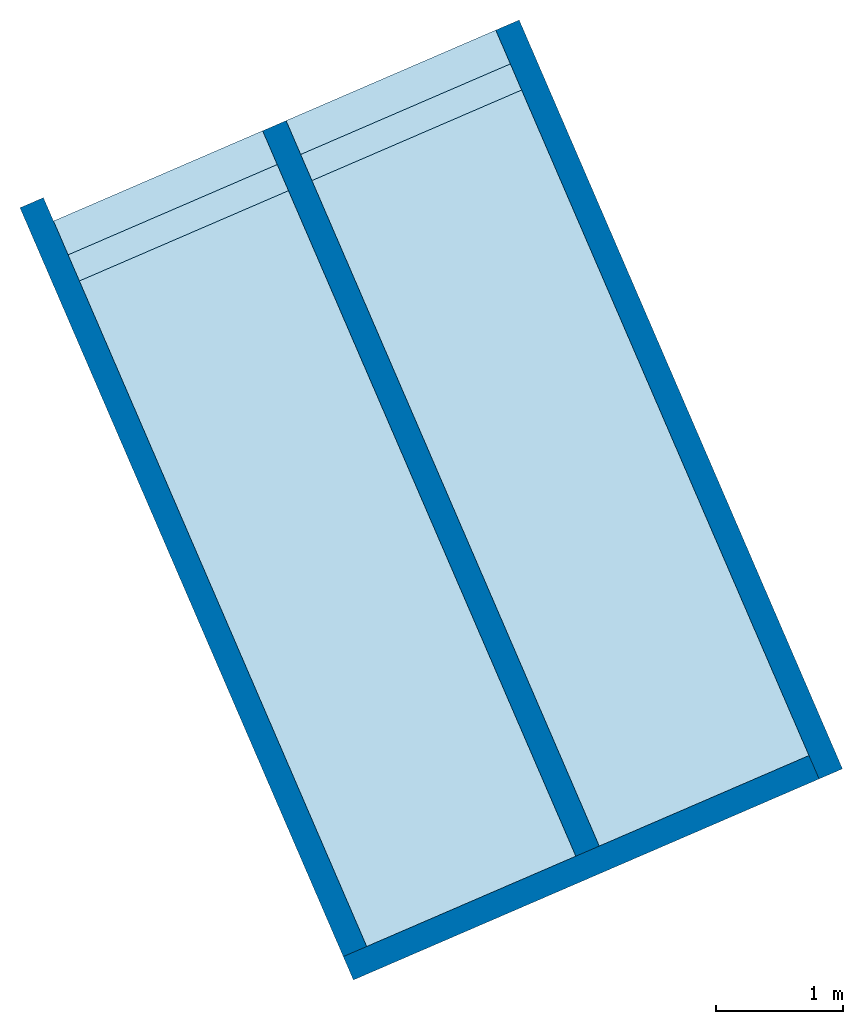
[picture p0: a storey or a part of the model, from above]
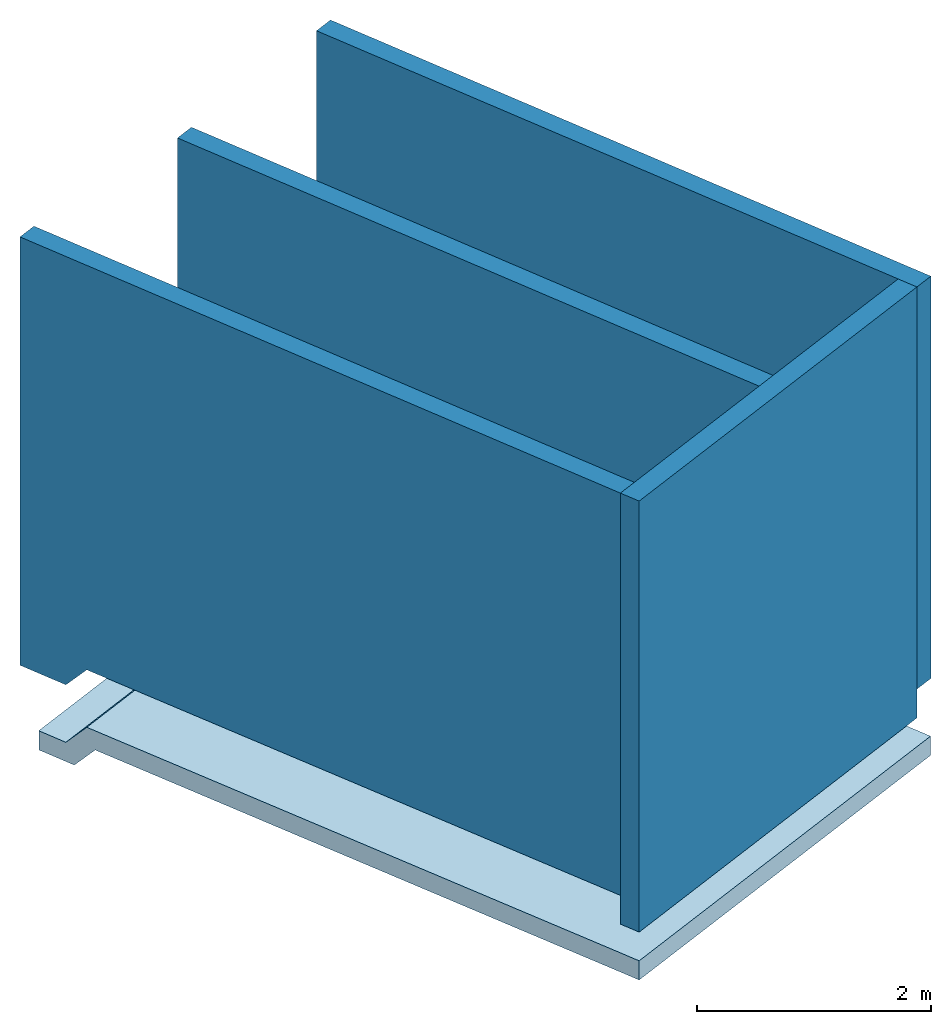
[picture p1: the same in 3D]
Properties of the parts of a building model (IFC4)

# File
Description: ViewDefinition [ReferenceView_V1.2], RevitIdentifiers [ContentGUID: b144eeac-5747-47a0-b632-81c9454398bd, VersionGUID: 75be5fcd-6818-4028-9b9e-a30bbd643937, NumberOfSaves: 4], CoordinateReference [CoordinateBase: Shared Coordinates, ProjectSite: Interno]
File name: C:\Users\Joaquin\Dropbox\BuildingProjects\2024 - Construcción Cesfam Coyhaique Con Sar Adosado\2_Modelos\all_models_2025-1-24_23.4.48\CCY_COOR-CCY_EST_tecnico_Enriched.ifc
Time: 2025-10-27T11:57:53-04:00
Written by: ODA SDAI 24.12
Made in: Autodesk Revit 25.4.30.30 (ENG) - IFC 25.4.3.0

# IfcProject, 2016_03
LongName: CESFAM Coyhaique; Phase: 2

# IfcSite, Default
RefLatitude: 42, 21, 31, 181945; RefLongitude: -71, -3, -24, -263305; RefElevation: 0 m
Pset_SiteCommon - Reference: Project Information
Other - Category: Project Information; Client Name: Servicio de Salud Aysén; Project Address: Calle 2, s/n. Lote 1C.; Project Issue Date: Marzo 2017; Project Name: CESFAM Coyhaique; Project Number: 2016_03; Project Status: 2
Identity Data - Author: Astudillo y Aparicio Asociados Ltda.; Building Name: CESFAM Coyhaique; Organization Description: Arquitectura e ingeniería integrada; Organization Name: Astudillo y Aparicio Asociados Ltda.

# IfcBuilding, CESFAM Coyhaique
LongName: CESFAM Coyhaique
Pset_BuildingCommon - Reference: Project Information; NumberOfStoreys: 6
Pset_BuildingElementProxyCommon - Reference: Project Information; IsExternal: no
Pset_BuildingSystemCommon - Reference: Project Information
Other - Category: Project Information; Client Name: Servicio de Salud Aysén; Project Address: Calle 2, s/n. Lote 1C.; Project Issue Date: Marzo 2017; Project Name: CESFAM Coyhaique; Project Number: 2016_03; Project Status: 2
Identity Data - Author: Astudillo y Aparicio Asociados Ltda.; Building Name: CESFAM Coyhaique; Organization Description: Arquitectura e ingeniería integrada; Organization Name: Astudillo y Aparicio Asociados Ltda.

# IfcBuildingStorey: Level:Nivel 8mm (6)
In: CESFAM Coyhaique
Other - Category: Levels; Family: Level; Family and Type: Level: Nivel 8mm; Type: Nivel 8mm; Type Id: 762418
Dimensions - Computation Height: 0 m
Identity Data - Structural: no; Building Story: yes
Other(Type) - Category: Levels; Family Name: Level
Constraints(Type) - Elevation Base: Survey Point
Graphics(Type) - Color: 0; Line Pattern: Center; Line Weight: 1; Symbol: Sim_NivelElev : Esc_200; Symbol at End 1 Default: no; Symbol at End 2 Default: yes
Identity Data(Type) - Type Name: Nivel 8mm
Name | LongName = Name | Elevation (m) | Constraints, Elevation (m)
Subterráneo 1 | Subterráneo 1 | -3.8 | 313.5
Base Estanques | Base Estanques | -3.55 | 313.75
Tunel | Tunel | -1.95 | 315.35
Nivel 1 | Nivel 1 | -0.55 | 316.75
Nivel 2 | Nivel 2 | 1.1 | 318.4
Nivel 3 | Nivel 3 | 2.7 | 320

# IfcBeam: M_W Shapes:W220X110mm (28)
In: Nivel 3
Type - PredefinedType: BEAM; Material: Steel, 45-345
Type - Other - Category: Structural Framing; Family Name: M_W Shapes
Type - Identity Data - Code Name: AISC 14.1; OmniClass Number: 23.25.30.11.14.14; OmniClass Title: Beams; Section Name Key: W12x26; Type Name: W220X110mm
Type - Structural - Section Shape: 6
Type - Structural Analysis - Elastic Modulus strong axis: 0.000547 m3; Elastic Modulus weak axis: 0.0000875 m3; Moment of Inertia strong axis: 0.0000849 m4; Moment of Inertia weak axis: 0.0000072 m4; Nominal Weight: 379.516 kg/s2; Perimeter: 1.25 m; Plastic Modulus strong axis: 0.00061 m3; Plastic Modulus weak axis: 0.000134 m3; Section Area: 0.00494 m2; Torsional Moment of Inertia: 1.25e-07 m4; Warping Constant: 1.63e-07 m6
Type - Structural Section Geometry - Centroid Horizontal: 0.055 m; Centroid Vertical: 0.11 m; Flange Thickness: 0.00965 m; Height: 0.22 m; Web Fillet: 0.00765 m; Web Thickness: 0.00584 m; Width: 0.11 m
Type - Pset_BeamCommon - LoadBearing: yes
Classification: B103 (FEMAP58); Material: Steel, 45-345; Steel, 45-345
Pset_BeamCommon - IsExternal: no; Reference: M_W Shapes:W220X110mm; Slope: 0 deg; Roll: 0 deg
Pset_EnvironmentalImpactIndicators - Reference: M_W Shapes:W220X110mm; sets with these values: 2
Qto_BeamBaseQuantities - CrossSectionArea: 0.00334538 m2
Other - Family: M_W Shapes; Family and Type: M_W Shapes: W220X110mm; Type: W220X110mm; Type Id: 849998
Constraints - Cross-Section Rotation: 0 deg; End Level Offset: 0 m; Orientation: Normal; Reference Level: Nivel 3; Reference Level Elevation: 2.7 m; Start Level Offset: 0 m; Work Plane: Level : Nivel 3
Dimensions - Elevation at Bottom: 2.33 m; Elevation at Top: 2.55 m
Materials and Finishes - Structural Material: Steel, 45-345
Phasing - Phase Created: New Construction
Structural - Stick Symbol Location: Center of Geometry; Structural Usage: Other
Geometric Position - Join Status: Both joins enabled; y Justification: Origin; y Offset Value: 0 m; yz Justification: Uniform; z Justification: Top; z Offset Value: -0.15 m
AboveGround - AboveGround: yes
Name (M_W Shapes:W220X110mm:...) | Span (m) = Qto_BeamBaseQuantities, Length (m) = Dimensions, Length (m) | OuterSurfaceArea (m2) | GrossSurfaceArea (m2) | NetSurfaceArea (m2) | GrossVolume (m3) | NetVolume (m3) = Volume (m3) | Cut Length (m) | Weight (kg) | End Extension (m) | Start Extension (m) | Start Join Cutback (m) | End Join Cutback (m)
833402 | 4.0749 | 3.4269 | 3.43359 | 3.43359 | 0.0134056 | 0.0134054 | 4.0072 | 155.376 | 0 | 0 | 0.0127
845368 | 3.98 | 3.28049 | 3.28719 | 3.28719 | 0.0128329 | 0.0128327 | 3.836 | 148.738 | -0.127 | -0.127
850091 | 1.05 | 0.887085 | 0.893776 | 0.893776 | 0.00347016 | 0.00347011 | 1.0373 | 40.2206 | -0.0166152 | 0 |  | 0.0127
850224 | 1.05 | 0.782153 | 0.788844 | 0.788844 | 0.00305968 | 0.00305964 | 0.9146 | 35.463 | -0.0166152 | 0 | 0.0127 | 0.0127
850260 | 6.085 | 5.08802 | 5.09471 | 5.09471 | 0.0199037 | 0.0199076 | 5.9496 | 230.692 | -0.0166152 | 0 | 0.0127 | 0.0127
850262 | 6.085 | 5.08802 | 5.09471 | 5.09471 | 0.0199037 | 0.0199076 | 5.9496 | 230.692 | -0.0166152 | 0 | 0.0127 | 0.0127
850275 | 3.01 | 2.45832 | 2.46501 | 2.46501 | 0.00961662 | 0.00961854 | 2.8746 | 111.461 | -0.0166152 | 0 | 0.0127 | 0.0127
850277 | 3.01 | 2.45832 | 2.46501 | 2.46501 | 0.00961662 | 0.00961854 | 2.8746 | 111.461 | -0.0166152 | 0 | 0.0127 | 0.0127
850289 | 3.99 | 3.2964 | 3.30309 | 3.3031 | 0.0128951 | 0.0128977 | 3.8546 | 149.459 | -0.0166152 | 0 | 0.0127 | 0.0127
850291 | 3.99 | 3.2964 | 3.30309 | 3.3031 | 0.0128951 | 0.0128977 | 3.8546 | 149.459 | -0.0166152 | 0 | 0.0127 | 0.0127
850303 | 5 | 4.16014 | 4.16683 | 4.16683 | 0.0162739 | 0.0162772 | 4.8646 | 188.621 | -0.0166152 | 0 | 0.0127 | 0.0127
850305 | 5 | 4.16014 | 4.16683 | 4.16683 | 0.0162739 | 0.0162772 | 4.8646 | 188.621 | -0.0166152 | 0 | 0.0127 | 0.0127
850319 | 4.2 | 3.47599 | 3.48268 | 3.48269 | 0.0135976 | 0.0136003 | 4.0646 | 157.602 | -0.0166152 | 0 | 0.0127 | 0.0127
850321 | 4.2 | 3.47599 | 3.48268 | 3.48269 | 0.0135976 | 0.0136003 | 4.0646 | 157.602 | -0.0166152 | 0 | 0.0127 | 0.0127
850335 | 4 | 3.30495 | 3.31164 | 3.31165 | 0.0129285 | 0.0129311 | 3.8646 | 149.847 | -0.0166152 | 0 | 0.0127 | 0.0127
850337 | 4 | 3.30495 | 3.31164 | 3.31165 | 0.0129285 | 0.0129311 | 3.8646 | 149.847 | -0.0166152 | 0 | 0.0127 | 0.0127
850355 | 4.4 | 3.64703 | 3.65372 | 3.65372 | 0.0142667 | 0.0142695 | 4.2646 | 165.357 | -0.0166152 | 0 | 0.0127 | 0.0127
850357 | 4.4 | 3.64703 | 3.65372 | 3.65372 | 0.0142667 | 0.0142695 | 4.2646 | 165.357 | -0.0166152 | 0 | 0.0127 | 0.0127
850370 | 2.785 | 2.2659 | 2.27259 | 2.2726 | 0.00886391 | 0.00886568 | 2.6496 | 102.736 | -0.0166152 | 0 | 0.0127 | 0.0127
850372 | 2.785 | 2.2659 | 2.27259 | 2.2726 | 0.00886391 | 0.00886568 | 2.6496 | 102.736 | -0.0166152 | 0 | 0.0127 | 0.0127
850586 | 3.98 | 3.28049 | 3.28719 | 3.28719 | 0.0128329 | 0.0128327 | 3.836 | 148.738 | -0.127 | -0.127
850598 | 3.98 | 3.28049 | 3.28719 | 3.28719 | 0.0128329 | 0.0128327 | 3.836 | 148.738 | -0.127 | -0.127
850610 | 3.98 | 3.28049 | 3.28719 | 3.28719 | 0.0128329 | 0.0128327 | 3.836 | 148.738 | -0.127 | -0.127
850622 | 3.98 | 3.28049 | 3.28719 | 3.28719 | 0.0128329 | 0.0128327 | 3.836 | 148.738 | -0.127 | -0.127
850634 | 3.98 | 3.28049 | 3.28719 | 3.28719 | 0.0128329 | 0.0128327 | 3.836 | 148.738 | -0.127 | -0.127
850646 | 3.98 | 3.28049 | 3.28719 | 3.28719 | 0.0128329 | 0.0128327 | 3.836 | 148.738 | -0.127 | -0.127
850658 | 3.98 | 3.28049 | 3.28719 | 3.28719 | 0.0128329 | 0.0128327 | 3.836 | 148.738 | -0.127 | -0.127
850670 | 3.98 | 3.28049 | 3.28719 | 3.28719 | 0.0128329 | 0.0128327 | 3.836 | 148.738 | -0.127 | -0.127

# IfcColumn: M_Concrete-Square-Column:600 x 600mm (7)
In: Subterráneo 1
Type - PredefinedType: COLUMN; Material: HA
Type - Other - Category: Structural Columns; Family Name: M_Concrete-Square-Column
Type - Data - Sup. en planta: 0.36 m2
Type - Dimensions - b: 0.6 m
Type - Identity Data - OmniClass Number: 23.25.30.11.14.11; OmniClass Title: Columns; Type Name: 600 x 600mm
Type - Structural - Section Shape: 0
Type - Pset_ColumnCommon - LoadBearing: yes
Classification: B1041 (FEMAP58); Material: HA; HA
Pset_ColumnCommon - IsExternal: no; Reference: M_Concrete-Square-Column:600 x 600mm
Pset_EnvironmentalImpactIndicators - Reference: M_Concrete-Square-Column:600 x 600mm; sets with these values: 2
Other - Family: M_Concrete-Square-Column; Family and Type: M_Concrete-Square-Column: 600 x 600mm; Type: 600 x 600mm; Type Id: 221304
Constraints - Base Offset: 0 m; Room Bounding: yes; Top Offset: 0 m; Level: Subterráneo 1; Column Style: Vertical; Moves With Grids: yes; Base Level: Subterráneo 1; Top Level: Nivel 1
Dimensions - Length: 3.25 m
Materials and Finishes - Structural Material: HA
Phasing - Phase Created: New Construction
Structural - Rebar Cover - Bottom Face: Rebar Cover 1 <25 mm>; Rebar Cover - Other Faces: Rebar Cover 1 <25 mm>; Rebar Cover - Top Face: Rebar Cover 1 <25 mm>
AboveGround - AboveGround: yes
Name (M_Concrete-Square-Column:600 x 600mm:...) | Length (m) | CrossSectionArea (m2) | OuterSurfaceArea (m2) | GrossVolume (m3) = NetVolume (m3) = Volume (m3) | Column Location Mark
845648 | 3.25 | 0.36 | 7.8 | 1.17 | K-X3
845900 | 3.25 | 0.36 | 7.8 | 1.17 | I-X3
846473 | 0.6 | 1.92 | 4.62 | 1.152 | I-X4
847178 | 0.6 | 1.92 | 4.62 | 1.152 | I-X5
847191 | 0.6 | 1.92 | 4.62 | 1.152 | I-X6
847208 | 0.6 | 1.92 | 4.62 | 1.152 | I-X7
847221 | 0.6 | 1.92 | 4.62 | 1.152 | I-X8

# IfcColumn: M_HP-Bearing Pile-Column:HP250X85 (18)
In: Nivel 1
Type - PredefinedType: COLUMN; Material: Steel, 45-345
Type - Other - Category: Structural Columns; Family Name: M_HP-Bearing Pile-Column
Type - Dimensions - bf: 0.26 m; d: 0.254 m; k: 0.032 m; kr: 0.0176 m; tf: 0.0144 m; tw: 0.0144 m
Type - Identity Data - OmniClass Number: 23.25.30.11.14.11; OmniClass Title: Columns; Type Name: HP250X85
Type - Structural - A: 0.0108 m2; Section Shape: 0; W: 0.832
Type - Pset_ColumnCommon - LoadBearing: yes
Classification: B1031 (FEMAP58); Material: Steel, 45-345; Steel, 45-345
Qto_ColumnBaseQuantities - Length: 3.1 m; CrossSectionArea: 0.010997 m2; OuterSurfaceArea: 4.61585 m2; GrossVolume: 0.0340906 m3; NetVolume: 0.0340921 m3
Pset_ColumnCommon - IsExternal: no; Reference: M_HP-Bearing Pile-Column:HP250X85
Pset_EnvironmentalImpactIndicators - Reference: M_HP-Bearing Pile-Column:HP250X85; sets with these values: 2
Other - Family: M_HP-Bearing Pile-Column; Family and Type: M_HP-Bearing Pile-Column: HP250X85; Type: HP250X85; Type Id: 831893
Constraints - Base Offset: 0 m; Level: Nivel 1; Base Level: Nivel 1; Column Style: Vertical; Moves With Grids: yes; Top Level: Nivel 3; Top Offset: -0.15 m
Dimensions - Length: 3.1 m; Volume: 0.0340921 m3
Materials and Finishes - Structural Material: Steel, 45-345
Phasing - Phase Created: New Construction
Structural - Weight: 0 kg
AboveGround - AboveGround: yes
Name (M_HP-Bearing Pile-Column:HP250X85:...) | Column Location Mark
832539 | K-X3
832541 | I-X3
832695 | K-X9
832697 | I-X9
832922 | K-X8
832924 | I-X8
832948 | K-X7
832950 | I-X7
832974 | K-X6
832976 | I-X6
832998 | K-X5
833000 | I-X5
833024 | K-X4
833026 | I-X4
844292 | K-X10
844294 | I-X10
844312 | K-X11
844314 | I-X11

# IfcGrid (6)
AboveGround - AboveGround: yes
Name | In
Default Grid | Subterráneo 1
Default Grid | Base Estanques
Default Grid | Tunel
Default Grid | Nivel 1
Default Grid | Nivel 2
Default Grid | Nivel 3

# IfcOpeningElement (9)
PredefinedType: OPENING
Pset_EnvironmentalImpactIndicators - sets with these values: 2
Other - Category: Lines: <Sketch>
Name | In | Height (m) | Width (m) | Reference | Length (m) | Concrete Cantilever (m) = Steel Cantilever (m) = Offset From Base (m) | Defines Constant Height = Defines Slope | Slope
Basic Wall:Contención-HA_200mm:533182 | Subterráneo 1 | 0.3 | 3.25 | Basic Wall:Contención-HA_200mm | 0.3
Floor:Losa HA 150mm:768037 | Nivel 1 | 1.30533 | 0.6 | Floor:Losa HA 150mm | 1.30533 | 0 | no | 0.0833333
3 x Floor:Losa HA 150mm:768037 | Nivel 1 | 1.30533 | 0.935 | Floor:Losa HA 150mm | 1.30533 | 0 | no | 0.0833333
Floor:Losa HA 150mm:768037 | Nivel 1 | 1.30533 | 1.5 | Floor:Losa HA 150mm | 1.30533 | 0 | no | 0.0833333
3 x Basic Wall:Contención-HA_200mm:533182 | Base Estanques |  |  | Basic Wall:Contención-HA_200mm | 0.335216 | Qto_OpeningElementBaseQuantities - Area: 1.54129 m2

# IfcSlab: Floor:Losa HA 150mm (2)
Type - PredefinedType: FLOOR; Material: HA
Type - Other - Category: Floors; Family Name: Floor
Type - Construction - Default Thickness: 0.15 m; Function: Interior
Type - Graphics - Coarse Scale Fill Color: 0
Type - Identity Data - Type Name: Losa HA 150mm
Type - Materials and Finishes - Structural Material: HA
Type - Analytical Properties - Absorptance: 0.1; Roughness: 1
Classification: B104 (FEMAP58)
Pset_EnvironmentalImpactIndicators - Reference: Floor:Losa HA 150mm; sets with these values: 2
Pset_SlabCommon - Reference: Floor:Losa HA 150mm; PitchAngle: 0 deg; IsExternal: no; LoadBearing: yes
Qto_SlabBaseQuantities - Depth: 0.15 m
Other - Family: Floor; Family and Type: Floor: Losa HA 150mm; Type: Losa HA 150mm; Type Id: 768037
Constraints - Related to Mass: no; Room Bounding: yes; Height Offset From Level: 0 m
Dimensions - Core Thickness: 0.15 m; Thickness: 0.15 m
Phasing - Phase Created: New Construction
Structural - Rebar Cover - Bottom Face: Rebar Cover 1 <25 mm>; Rebar Cover - Other Faces: Rebar Cover 1 <25 mm>; Rebar Cover - Top Face: Rebar Cover 1 <25 mm>; Structural: yes
AboveGround - AboveGround: yes
Name (Floor:Losa HA 150mm:...) | In | Qto_SlabBaseQuantities, Perimeter (m) | GrossArea (m2) | NetArea (m2) = Area (m2) | GrossVolume (m3) | NetVolume (m3) = Volume (m3) | Level | Elevation at Bottom (m) = Elevation at Bottom Core (m) | Elevation at Bottom Survey (m) | Elevation at Top (m) = Elevation at Top Core (m) | Elevation at Top Survey (m) | Dimensions, Perimeter (m)
796040 | Nivel 1 | 247.06 | 41.505 | 35.1024 | 6.22575 | 5.26536 | Nivel 1 | -0.7 | 316.6 | -0.55 | 316.75 | 75.3039
828070 | Tunel | 97.3417 | 24.5763 | 24.5763 | 3.68644 | 3.68644 | Tunel | -2.1 | 315.2 | -1.95 | 315.35 | 29.6698 | Qto_SlabBaseQuantities - Width: 1.9 m; Length: 12.9349 m

# IfcSlab: Floor:Losa colaborante 150mm, Floor:Losa colaborante 150mm:830483
In: Nivel 3
Type - PredefinedType: FLOOR; Material: HA
Type - Other - Category: Floors; Family Name: Floor
Type - Construction - Function: Interior; Default Thickness: 0.15 m
Type - Graphics - Coarse Scale Fill Color: 0
Type - Identity Data - Type Name: Losa colaborante 150mm
Type - Materials and Finishes - Structural Material: HA
Type - Analytical Properties - Absorptance: 0.1; Roughness: 1; Heat Transfer Coefficient (U): 1000000000000000019884624838656 kg/K/s3; Thermal Mass: 0; Thermal Resistance (R): 0 s3*K/kg
Type - Pset_SlabCommon - ThermalTransmittance: 1000000000000000019884624838656 kg/K/s3
Classification: B104 (FEMAP58)
Pset_EnvironmentalImpactIndicators - Reference: Floor:Losa colaborante 150mm; sets with these values: 2
Pset_SlabCommon - PitchAngle: 0 deg; IsExternal: no; LoadBearing: yes; Reference: Floor:Losa colaborante 150mm
Qto_SlabBaseQuantities - HA, Width: 0.15 m; Width: 0.15 m; Length: 4.175 m; Depth: 0.15 m; Perimeter: 255.217 m; GrossArea: 144.956 m2; NetArea: 144.956 m2; GrossVolume: 21.7434 m3; NetVolume: 21.7434 m3
Other - Family: Floor; Family and Type: Floor: Losa colaborante 150mm; Type: Losa colaborante 150mm; Type Id: 809659
Constraints - Related to Mass: no; Room Bounding: yes; Height Offset From Level: 0 m; Level: Nivel 3
Dimensions - Area: 144.956 m2; Core Thickness: 0.15 m; Elevation at Bottom: 2.55 m; Elevation at Bottom Core: 2.55 m; Elevation at Bottom Survey: 319.85 m; Elevation at Top: 2.7 m; Elevation at Top Core: 2.7 m; Elevation at Top Survey: 320 m; Perimeter: 77.79 m; Thickness: 0.15 m; Volume: 21.7434 m3
Phasing - Phase Created: New Construction
Structural - Rebar Cover - Bottom Face: Rebar Cover 1 <25 mm>; Rebar Cover - Other Faces: Rebar Cover 1 <25 mm>; Rebar Cover - Top Face: Rebar Cover 1 <25 mm>; Structural: yes
AboveGround - AboveGround: yes

# IfcSlab: Floor:LosaHA - 150mm, Floor:LosaHA - 150mm:820109
In: Nivel 2
Type - PredefinedType: FLOOR; Material: HA
Type - Other - Category: Floors; Family Name: Floor
Type - Construction - Function: Interior; Default Thickness: 0.15 m
Type - Graphics - Coarse Scale Fill Color: 0
Type - Identity Data - Type Name: LosaHA - 150mm
Type - Materials and Finishes - Structural Material: HA
Type - Analytical Properties - Absorptance: 0.1; Roughness: 1
Classification: B104 (FEMAP58)
Pset_EnvironmentalImpactIndicators - Reference: Floor:LosaHA - 150mm; sets with these values: 2
Pset_SlabCommon - PitchAngle: 0 deg; IsExternal: no; LoadBearing: yes; Reference: Floor:LosaHA - 150mm
Qto_SlabBaseQuantities - Width: 6.62334 m; Length: 4.175 m; Depth: 0.15 m; Perimeter: 70.8553 m; GrossArea: 27.6525 m2; NetArea: 27.6525 m2; GrossVolume: 4.14787 m3; NetVolume: 4.14787 m3
Other - Family: Floor; Family and Type: Floor: LosaHA - 150mm; Type: LosaHA - 150mm; Type Id: 226016
Constraints - Related to Mass: no; Room Bounding: yes; Height Offset From Level: 0 m; Level: Nivel 2
Dimensions - Area: 27.6525 m2; Core Thickness: 0.15 m; Elevation at Bottom: 0.949999 m; Elevation at Bottom Core: 0.949999 m; Elevation at Bottom Survey: 318.25 m; Elevation at Top: 1.1 m; Elevation at Top Core: 1.1 m; Elevation at Top Survey: 318.4 m; Perimeter: 21.5967 m; Thickness: 0.15 m; Volume: 4.14787 m3
Phasing - Phase Created: New Construction
Structural - Rebar Cover - Bottom Face: Rebar Cover 1 <25 mm>; Rebar Cover - Other Faces: Rebar Cover 1 <25 mm>; Rebar Cover - Top Face: Rebar Cover 1 <25 mm>; Structural: yes
AboveGround - AboveGround: yes

# IfcSlab: Floor:Radier - 100mm, Floor:Radier - 100mm:830206
In: Nivel 1
Type - PredefinedType: FLOOR; Material: HA
Type - Other - Category: Floors; Family Name: Floor
Type - Construction - Function: Interior; Default Thickness: 0.1 m
Type - Graphics - Coarse Scale Fill Color: 0
Type - Identity Data - Type Name: Radier - 100mm
Type - Materials and Finishes - Structural Material: HA
Type - Analytical Properties - Absorptance: 0.1; Roughness: 1
Classification: B104 (FEMAP58)
Pset_EnvironmentalImpactIndicators - Reference: Floor:Radier - 100mm; sets with these values: 2
Pset_SlabCommon - PitchAngle: 0 deg; IsExternal: no; LoadBearing: yes; Reference: Floor:Radier - 100mm
Qto_SlabBaseQuantities - Depth: 0.1 m; Perimeter: 238.944 m; GrossArea: 88.4143 m2; NetArea: 88.4143 m2; GrossVolume: 8.84143 m3; NetVolume: 8.84143 m3
Other - Family: Floor; Family and Type: Floor: Radier - 100mm; Type: Radier - 100mm; Type Id: 514839
Constraints - Related to Mass: no; Room Bounding: yes; Height Offset From Level: 0 m; Level: Nivel 1
Dimensions - Area: 88.4143 m2; Core Thickness: 0.1 m; Elevation at Bottom: -0.65 m; Elevation at Bottom Core: -0.65 m; Elevation at Bottom Survey: 316.65 m; Elevation at Top: -0.55 m; Elevation at Top Core: -0.55 m; Elevation at Top Survey: 316.75 m; Perimeter: 72.83 m; Thickness: 0.1 m; Volume: 8.84143 m3
Phasing - Phase Created: New Construction
Structural - Rebar Cover - Bottom Face: Rebar Cover 1 <25 mm>; Rebar Cover - Other Faces: Rebar Cover 1 <25 mm>; Rebar Cover - Top Face: Rebar Cover 1 <25 mm>; Structural: yes
AboveGround - AboveGround: yes

# IfcSlab: Foundation Slab:150mm Foundation Slab (2)
In: Subterráneo 1
Type - PredefinedType: BASESLAB; Material: HA
Type - Other - Category: Structural Foundations; Family Name: Foundation Slab
Type - Construction - Default Thickness: 0.15 m
Type - Dimensions - Foundation Thickness: 0.15 m
Type - Graphics - Coarse Scale Fill Color: 0
Type - Identity Data - Type Name: 150mm Foundation Slab
Type - Materials and Finishes - Structural Material: HA
Type - Analytical Properties - Absorptance: 0.1; Roughness: 1
Classification: Foundation (FEMAP58)
Pset_EnvironmentalImpactIndicators - Reference: Foundation Slab:150mm Foundation Slab; sets with these values: 2
Pset_SlabCommon - PitchAngle: 0 deg; IsExternal: no; LoadBearing: yes; Reference: Foundation Slab:150mm Foundation Slab
Qto_SlabBaseQuantities - Depth: 0.15 m
Other - Family: Foundation Slab; Family and Type: Foundation Slab: 150mm Foundation Slab; Type: 150mm Foundation Slab; Type Id: 109351
Constraints - Related to Mass: no; Height Offset From Level: 0 m; Level: Subterráneo 1
Dimensions - Core Thickness: 0.15 m; Elevation at Bottom: -3.95 m; Elevation at Bottom Core: -3.95 m; Elevation at Bottom Survey: 313.35 m; Elevation at Top: -3.8 m; Elevation at Top Core: -3.8 m; Elevation at Top Survey: 313.5 m; Thickness: 0.15 m
Phasing - Phase Created: New Construction
Structural - Rebar Cover - Bottom Face: Rebar Cover 1 <25 mm>; Rebar Cover - Other Faces: Rebar Cover 1 <25 mm>; Rebar Cover - Top Face: Rebar Cover 1 <25 mm>; Structural: yes
Name (Foundation Slab:150mm Foundation Slab:...) | Qto_SlabBaseQuantities, Width (m) = Dimensions, Width (m) | Qto_SlabBaseQuantities, Length (m) = Dimensions, Length (m) | Qto_SlabBaseQuantities, Perimeter (m) | GrossArea (m2) = NetArea (m2) = Area (m2) | GrossVolume (m3) = NetVolume (m3) = Volume (m3) | Dimensions, Perimeter (m)
812009 | 4.18 | 26.6 | 213.78 | 48.6912 | 7.30368 | 65.16
849104 | 1.9 | 14.835 | 109.81 | 28.1066 | 4.21599 | 33.4701

# IfcSlab: Foundation Slab:200mm Foundation Slab, Foundation Slab:200mm Foundation Slab:825862
In: Subterráneo 1
Type - PredefinedType: BASESLAB; Material: HA
Type - Other - Category: Structural Foundations; Family Name: Foundation Slab
Type - Construction - Default Thickness: 0.2 m
Type - Dimensions - Foundation Thickness: 0.2 m
Type - Graphics - Coarse Scale Fill Color: 0
Type - Identity Data - Type Name: 200mm Foundation Slab
Type - Materials and Finishes - Structural Material: HA
Type - Analytical Properties - Absorptance: 0.1; Roughness: 1
Classification: Foundation (FEMAP58)
Pset_EnvironmentalImpactIndicators - Reference: Foundation Slab:200mm Foundation Slab; sets with these values: 2
Pset_SlabCommon - PitchAngle: 0 deg; IsExternal: no; LoadBearing: yes; Reference: Foundation Slab:200mm Foundation Slab
Qto_SlabBaseQuantities - Width: 1.25 m; Length: 1.405 m; Depth: 0.2 m; Perimeter: 17.4213 m; GrossArea: 1.75625 m2; NetArea: 1.75625 m2; GrossVolume: 0.35125 m3; NetVolume: 0.35125 m3
Other - Family: Foundation Slab; Family and Type: Foundation Slab: 200mm Foundation Slab; Type: 200mm Foundation Slab; Type Id: 828325
Constraints - Related to Mass: no; Level: Subterráneo 1; Height Offset From Level: -0.4 m
Dimensions - Area: 1.75625 m2; Core Thickness: 0.2 m; Elevation at Bottom: -4.4 m; Elevation at Bottom Core: -4.4 m; Elevation at Bottom Survey: 312.9 m; Elevation at Top: -4.2 m; Elevation at Top Core: -4.2 m; Elevation at Top Survey: 313.1 m; Length: 1.405 m; Perimeter: 5.31 m; Thickness: 0.2 m; Volume: 0.35125 m3; Width: 1.25 m
Phasing - Phase Created: New Construction
Structural - Rebar Cover - Bottom Face: Rebar Cover 1 <25 mm>; Rebar Cover - Other Faces: Rebar Cover 1 <25 mm>; Rebar Cover - Top Face: Rebar Cover 1 <25 mm>; Structural: yes

# IfcSlab: Losa base estanques:Losa base estanques, Losa base estanques:Losa base estanques:827730
In: Base Estanques
Type - PredefinedType: FLOOR; Material: HA
Type - Other - Category: Floors; Family Name: Losa base estanques
Type - Identity Data - Type Name: Losa base estanques
Type - Materials and Finishes - Structural Material: HA
Pset_EnvironmentalImpactIndicators - Reference: Losa base estanques:Losa base estanques; sets with these values: 2
Pset_SlabCommon - IsExternal: no; Reference: Losa base estanques:Losa base estanques
Qto_SlabBaseQuantities - Depth: 4.175 m; Perimeter: 13.4241 m; GrossArea: 1.30241 m2; NetArea: 1.30241 m2; GrossVolume: 5.43756 m3; NetVolume: 5.43756 m3
Other - Family: Losa base estanques; Family and Type: Losa base estanques: Losa base estanques; Type: Losa base estanques; Type Id: 827728
Constraints - Room Bounding: yes; Elevation from Level: 0.2 m; Level: Base Estanques; Moves With Nearby Elements: no
Dimensions - Area: 1.30241 m2; Volume: 5.43756 m3
Phasing - Phase Created: New Construction
Structural - Rebar Cover: Rebar Cover 1 <25 mm>
AboveGround - AboveGround: yes

# IfcWall: Basic Wall:Contención-HA_200mm (33)
Type - PredefinedType: STANDARD
Type - Other - Category: Walls; Family Name: Basic Wall
Type - Construction - Function: Exterior; Width: 0.2 m; Wrapping at Ends: Exterior; Wrapping at Inserts: Exterior
Type - Graphics - Coarse Scale Fill Color: 6974058
Type - Identity Data - Description: Maó calat (gero) e=14 cm; Model: M03; Type Name: Contención-HA_200mm
Type - Materials and Finishes - Structural Material: HA
Type - Analytical Properties - Absorptance: 0.1; Roughness: 1
Type - Pset_ReinforcementBarPitchOfWall - Description: Maó calat (gero) e=14 cm
Classification: B2011 (FEMAP58); Material: HA
Qto_WallBaseQuantities - Width: 0.2 m
Pset_EnvironmentalImpactIndicators - Reference: Basic Wall:Contención-HA_200mm; sets with these values: 2
Pset_WallCommon - Reference: Basic Wall:Contención-HA_200mm; IsExternal: yes; LoadBearing: no; ExtendToStructure: no
Other - Family: Basic Wall; Family and Type: Basic Wall: Contención-HA_200mm; Type: Contención-HA_200mm; Type Id: 533182
Constraints - Base Extension Distance: 0 m; Base is Attached: no; Location Line: Wall Centerline; Related to Mass: no; Room Bounding: yes; Top Extension Distance: 0 m; Top is Attached: no
Phasing - Phase Created: New Construction
Structural - Structural: no; Structural Usage: Non-bearing
Cross-Section Definition - Cross-Section: Vertical
AboveGround - AboveGround: yes
Name (Basic Wall:Contención-HA_200mm:...) | In | Height (m) | Qto_WallBaseQuantities, Length (m) | GrossFootprintArea (m2) | GrossVolume (m3) | GrossSideArea (m2) = NetSideArea (m2) | NetVolume (m3) = Volume (m3) | Pset_WallArea, Area (m2) = Dimensions, Area (m2) | Pset_WallLength, Length (m) = Dimensions, Length (m) | Base Constraint | Base Offset (m) | Top Constraint | Top Offset (m) | Unconnected Height (m)
795761 | Subterráneo 1 | 3.1 | 24.115 | 4.823 | 14.9513 | 74.7565 | 14.9513 | 74.7565 | 24.115 | Subterráneo 1 | 0 | Up to level: Nivel 1 | -0.15 | 3.1
795762 | Subterráneo 1 | 1.85 | 13.0349 | 2.60698 | 4.43786 | 22.1893 | 4.43786 | 22.1893 | 12.9349 | Subterráneo 1 | 0 |  | -1.3 | 1.85
795763 | Subterráneo 1 | 2.1 | 1.5 | 0.3 | 0.63 | 3.15 | 0.63 | 3.15 | 1.7 | Subterráneo 1 | 0 | Up to level: Tunel | 0.25 | 2.1
795764 | Subterráneo 1 | 1.85 | 13.0349 | 2.60698 | 4.43786 | 22.1893 | 4.43786 | 22.1893 | 12.9349 | Subterráneo 1 | 0 |  | -1.3 | 1.85
795821 | Subterráneo 1 | 3.1 | 1.70533 | 0.341065 | 1.0573 | 5.28651 | 1.0573 | 5.28651 | 1.50533 | Subterráneo 1 | 0 | Up to level: Nivel 1 | -0.15 | 3.1
795877 | Subterráneo 1 | 3.7 | 0.85 | 0.17 | 0.499 | 2.495 | 0.499 | 2.495 | 0.75 | Subterráneo 1 | 0 | Up to level: Nivel 1 | 0 | 3.25
795976 | Subterráneo 1 |  | 1.725 |  |  |  | 1.0325 | 5.1625 | 1.725 | Subterráneo 1 | 0 | Up to level: Nivel 1 | -0.15 | 3.1
799060 | Subterráneo 1 |  | 1.70017 |  |  |  | 0.761071 | 3.80536 | 1.70017 | Subterráneo 1 | 0 | Up to level: Tunel | 0.25 | 2.1
799191 | Subterráneo 1 |  | 1.70017 |  |  |  | 0.761071 | 3.80536 | 1.70017 | Subterráneo 1 | 0 | Up to level: Tunel | 0.25 | 2.1
813726 | Subterráneo 1 | 0.7 | 1.9 | 0.38 | 0.266 | 1.33 | 0.266 | 1.33 | 1.7 | Subterráneo 1 | 2.7 |  | 0 | 0.7
814008 | Subterráneo 1 |  | 1.7 |  |  |  | 0.47 | 2.35 | 1.7 | Subterráneo 1 | 1.7 |  | -0.35 | 1.4
820015 | Base Estanques | 4.5 | 3.98 | 0.796 | 3.582 | 17.91 | 3.582 | 17.91 | 3.98 | Base Estanques | 0 | Up to level: Nivel 2 | -0.15 | 4.5
820016 | Base Estanques | 4.47253 | 6.2 | 1.24 | 5.24314 | 26.2157 | 5.24314 | 26.2157 | 6.4 | Base Estanques | 0 | Up to level: Nivel 2 | -0.15 | 4.5
820017 | Subterráneo 1 | 3.15 | 2.27467 | 0.454935 | 1.43304 | 7.16522 | 1.43304 | 7.16522 | 2.27467 | Subterráneo 1 | 0 | Up to level: Nivel 1 | 0 | 3.25
822382 | Subterráneo 1 |  | 3.98 |  |  |  | 4.0209 | 20.1045 | 3.98 | Subterráneo 1 | -0.222533 | Up to level: Nivel 2 | -0.15 | 4.97253
822495 | Subterráneo 1 | 3.25 | 1.035 | 0.207 | 0.67275 | 3.36375 | 0.67275 | 3.36375 | 1.135 | Subterráneo 1 | 0 | Up to level: Nivel 1 | 0 | 3.25
823209 | Base Estanques | 4.47253 | 6.4 | 1.28 | 5.42204 | 27.1102 | 5.42204 | 27.1102 | 6.4 | Base Estanques | 0 | Up to level: Nivel 2 | -0.15 | 4.5
823391 | Base Estanques | 4.47253 | 6.4 | 1.28 | 5.41112 | 27.0556 | 5.41112 | 27.0556 | 6.4 | Base Estanques | 0 | Up to level: Nivel 2 | -0.15 | 4.5
826698 | Subterráneo 1 | 0.25 | 1.205 | 0.241 | 0.06025 | 0.30125 | 0.06025 | 0.30125 | 1.205 | Subterráneo 1 | -0.4 |  | 0 | 0.4
826973 | Subterráneo 1 |  | 1.05 |  |  |  | 0.103599 | 0.517993 | 1.05 | Subterráneo 1 | -0.45 |  | 0 | 0.45
828773 | Subterráneo 1 | 0.8 | 1.50533 | 0.301065 | 0.240852 | 1.20426 | 0.240852 | 1.20426 | 1.60533 | Subterráneo 1 | 0 |  | 0 | 0.8
842595 | Subterráneo 1 | 0.7 | 1.7 | 0.34 | 0.238 | 1.19 | 0.238 | 1.19 | 1.7 | Subterráneo 1 | 2.7 |  | 0 | 0.7
842834 | Subterráneo 1 | 0.7 | 1.5 | 0.3 | 0.21 | 1.05 | 0.21 | 1.05 | 1.6 | Subterráneo 1 | 2.7 |  | 0 | 0.7
842938 | Subterráneo 1 | 0.7 | 1.5 | 0.3 | 0.21 | 1.05 | 0.21 | 1.05 | 1.6 | Subterráneo 1 | 2.7 |  | 0 | 0.7
846069 | Subterráneo 1 | 3.25 | 0.65 | 0.13 | 0.4225 | 2.1125 | 0.4225 | 2.1125 | 0.75 | Subterráneo 1 | 0 | Up to level: Nivel 1 | 0 | 3.25
846267 | Subterráneo 1 | 3.25 | 1.235 | 0.247 | 0.79675 | 3.98375 | 0.79675 | 3.98375 | 1.235 | Subterráneo 1 | 0 | Up to level: Nivel 1 | 0 | 3.25
846577 | Subterráneo 1 | 3.1 | 2.41 | 0.482 | 1.4942 | 7.471 | 1.4942 | 7.471 | 2.41 | Subterráneo 1 | 0 | Up to level: Nivel 1 | 0 | 3.25
846883 | Subterráneo 1 | 3.1 | 4.25 | 0.85 | 2.635 | 13.175 | 2.635 | 13.175 | 4.25 | Subterráneo 1 | 0 | Up to level: Nivel 1 | 0 | 3.25
847279 | Subterráneo 1 |  | 0.975 |  |  |  | 0.5675 | 2.8375 | 0.975 | Subterráneo 1 | 0 | Up to level: Nivel 1 | 0 | 3.25
847463 | Subterráneo 1 | 3.1 | 3.39 | 0.678 | 2.1018 | 10.509 | 2.1018 | 10.509 | 3.39 | Subterráneo 1 | 0 | Up to level: Nivel 1 | 0 | 3.25
847621 | Subterráneo 1 | 3.1 | 3.6 | 0.72 | 2.232 | 11.16 | 2.232 | 11.16 | 3.6 | Subterráneo 1 | 0 | Up to level: Nivel 1 | -0.15 | 3.1
847755 | Subterráneo 1 | 3.1 | 2.865 | 0.573 | 1.7763 | 8.8815 | 1.7763 | 8.8815 | 2.965 | Subterráneo 1 | 0 | Up to level: Nivel 1 | -0.15 | 3.1
851194 | Subterráneo 1 | 0.25 | 1.5 | 0.3 | 0.075 | 0.375 | 0.075 | 0.375 | 1.7 | Subterráneo 1 | 1.85 |  | 0 | 0.25
